One B-rep face of a CAD part: STEP entity #52636.
In plain terms, the planar face has unit normal (0, -0.174, 0.985).
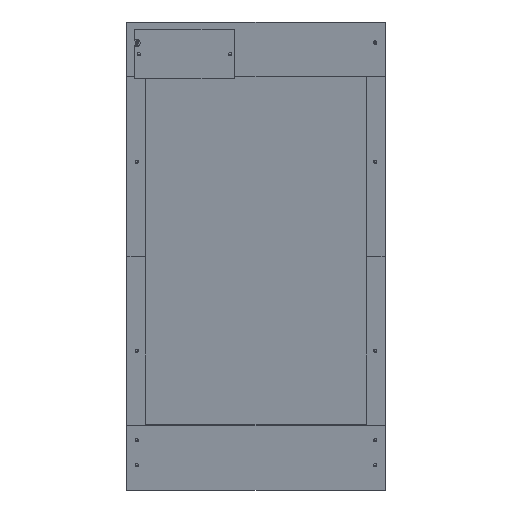
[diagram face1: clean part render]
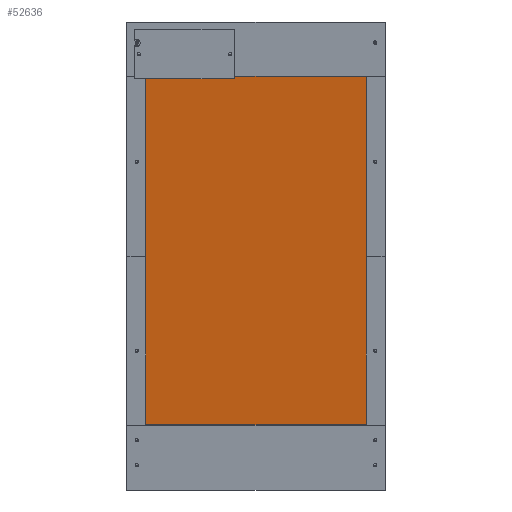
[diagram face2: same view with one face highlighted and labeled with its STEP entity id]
Its self-contained STEP definition (entity closure, numbers rounded to 3 decimals):
#52467 = PLANE('',#52468);
#52468 = AXIS2_PLACEMENT_3D('',#52469,#52470,#52471);
#52469 = CARTESIAN_POINT('',(18.1,64.,86.285));
#52470 = DIRECTION('',(-0.,1.,0.));
#52471 = DIRECTION('',(0.,0.,-1.));
#52495 = PLANE('',#52496);
#52496 = AXIS2_PLACEMENT_3D('',#52497,#52498,#52499);
#52497 = CARTESIAN_POINT('',(241.9,240.675,111.437));
#52498 = DIRECTION('',(1.,0.,0.));
#52499 = DIRECTION('',(-0.,0.,1.));
#52523 = PLANE('',#52524);
#52524 = AXIS2_PLACEMENT_3D('',#52525,#52526,#52527);
#52525 = CARTESIAN_POINT('',(18.1,417.349,136.59));
#52526 = DIRECTION('',(0.,-1.,0.));
#52527 = DIRECTION('',(0.,0.,1.));
#52549 = PLANE('',#52550);
#52550 = AXIS2_PLACEMENT_3D('',#52551,#52552,#52553);
#52551 = CARTESIAN_POINT('',(18.1,240.675,111.437));
#52552 = DIRECTION('',(1.,0.,0.));
#52553 = DIRECTION('',(-0.,0.,1.));
#52566 = VERTEX_POINT('',#52567);
#52567 = CARTESIAN_POINT('',(241.9,417.349,148.59));
#52588 = EDGE_CURVE('',#52589,#52566,#52591,.T.);
#52589 = VERTEX_POINT('',#52590);
#52590 = CARTESIAN_POINT('',(18.1,417.349,148.59));
#52591 = SURFACE_CURVE('',#52592,(#52596,#52603),.PCURVE_S1.);
#52592 = LINE('',#52593,#52594);
#52593 = CARTESIAN_POINT('',(18.1,417.349,148.59));
#52594 = VECTOR('',#52595,1.);
#52595 = DIRECTION('',(1.,0.,0.));
#52596 = PCURVE('',#52523,#52597);
#52597 = DEFINITIONAL_REPRESENTATION('',(#52598),#52602);
#52598 = LINE('',#52599,#52600);
#52599 = CARTESIAN_POINT('',(12.,0.));
#52600 = VECTOR('',#52601,1.);
#52601 = DIRECTION('',(0.,-1.));
#52602 = ( GEOMETRIC_REPRESENTATION_CONTEXT(2) 
PARAMETRIC_REPRESENTATION_CONTEXT() REPRESENTATION_CONTEXT('2D SPACE',''
  ) );
#52603 = PCURVE('',#52604,#52609);
#52604 = PLANE('',#52605);
#52605 = AXIS2_PLACEMENT_3D('',#52606,#52607,#52608);
#52606 = CARTESIAN_POINT('',(18.1,417.349,148.59));
#52607 = DIRECTION('',(0.,0.174,-0.985));
#52608 = DIRECTION('',(0.,-0.985,-0.174));
#52609 = DEFINITIONAL_REPRESENTATION('',(#52610),#52614);
#52610 = LINE('',#52611,#52612);
#52611 = CARTESIAN_POINT('',(0.,0.));
#52612 = VECTOR('',#52613,1.);
#52613 = DIRECTION('',(0.,-1.));
#52614 = ( GEOMETRIC_REPRESENTATION_CONTEXT(2) 
PARAMETRIC_REPRESENTATION_CONTEXT() REPRESENTATION_CONTEXT('2D SPACE',''
  ) );
#52636 = ADVANCED_FACE('',(#52637),#52604,.F.);
#52637 = FACE_BOUND('',#52638,.F.);
#52638 = EDGE_LOOP('',(#52639,#52640,#52663,#52686));
#52639 = ORIENTED_EDGE('',*,*,#52588,.T.);
#52640 = ORIENTED_EDGE('',*,*,#52641,.T.);
#52641 = EDGE_CURVE('',#52566,#52642,#52644,.T.);
#52642 = VERTEX_POINT('',#52643);
#52643 = CARTESIAN_POINT('',(241.9,64.,86.285));
#52644 = SURFACE_CURVE('',#52645,(#52649,#52656),.PCURVE_S1.);
#52645 = LINE('',#52646,#52647);
#52646 = CARTESIAN_POINT('',(241.9,417.349,148.59));
#52647 = VECTOR('',#52648,1.);
#52648 = DIRECTION('',(0.,-0.985,-0.174));
#52649 = PCURVE('',#52604,#52650);
#52650 = DEFINITIONAL_REPRESENTATION('',(#52651),#52655);
#52651 = LINE('',#52652,#52653);
#52652 = CARTESIAN_POINT('',(0.,-223.8));
#52653 = VECTOR('',#52654,1.);
#52654 = DIRECTION('',(1.,0.));
#52655 = ( GEOMETRIC_REPRESENTATION_CONTEXT(2) 
PARAMETRIC_REPRESENTATION_CONTEXT() REPRESENTATION_CONTEXT('2D SPACE',''
  ) );
#52656 = PCURVE('',#52495,#52657);
#52657 = DEFINITIONAL_REPRESENTATION('',(#52658),#52662);
#52658 = LINE('',#52659,#52660);
#52659 = CARTESIAN_POINT('',(37.152,-176.675));
#52660 = VECTOR('',#52661,1.);
#52661 = DIRECTION('',(-0.174,0.985));
#52662 = ( GEOMETRIC_REPRESENTATION_CONTEXT(2) 
PARAMETRIC_REPRESENTATION_CONTEXT() REPRESENTATION_CONTEXT('2D SPACE',''
  ) );
#52663 = ORIENTED_EDGE('',*,*,#52664,.F.);
#52664 = EDGE_CURVE('',#52665,#52642,#52667,.T.);
#52665 = VERTEX_POINT('',#52666);
#52666 = CARTESIAN_POINT('',(18.1,64.,86.285));
#52667 = SURFACE_CURVE('',#52668,(#52672,#52679),.PCURVE_S1.);
#52668 = LINE('',#52669,#52670);
#52669 = CARTESIAN_POINT('',(18.1,64.,86.285));
#52670 = VECTOR('',#52671,1.);
#52671 = DIRECTION('',(1.,0.,0.));
#52672 = PCURVE('',#52604,#52673);
#52673 = DEFINITIONAL_REPRESENTATION('',(#52674),#52678);
#52674 = LINE('',#52675,#52676);
#52675 = CARTESIAN_POINT('',(358.8,0.));
#52676 = VECTOR('',#52677,1.);
#52677 = DIRECTION('',(0.,-1.));
#52678 = ( GEOMETRIC_REPRESENTATION_CONTEXT(2) 
PARAMETRIC_REPRESENTATION_CONTEXT() REPRESENTATION_CONTEXT('2D SPACE',''
  ) );
#52679 = PCURVE('',#52467,#52680);
#52680 = DEFINITIONAL_REPRESENTATION('',(#52681),#52685);
#52681 = LINE('',#52682,#52683);
#52682 = CARTESIAN_POINT('',(0.,0.));
#52683 = VECTOR('',#52684,1.);
#52684 = DIRECTION('',(0.,-1.));
#52685 = ( GEOMETRIC_REPRESENTATION_CONTEXT(2) 
PARAMETRIC_REPRESENTATION_CONTEXT() REPRESENTATION_CONTEXT('2D SPACE',''
  ) );
#52686 = ORIENTED_EDGE('',*,*,#52687,.F.);
#52687 = EDGE_CURVE('',#52589,#52665,#52688,.T.);
#52688 = SURFACE_CURVE('',#52689,(#52693,#52700),.PCURVE_S1.);
#52689 = LINE('',#52690,#52691);
#52690 = CARTESIAN_POINT('',(18.1,417.349,148.59));
#52691 = VECTOR('',#52692,1.);
#52692 = DIRECTION('',(0.,-0.985,-0.174));
#52693 = PCURVE('',#52604,#52694);
#52694 = DEFINITIONAL_REPRESENTATION('',(#52695),#52699);
#52695 = LINE('',#52696,#52697);
#52696 = CARTESIAN_POINT('',(0.,0.));
#52697 = VECTOR('',#52698,1.);
#52698 = DIRECTION('',(1.,0.));
#52699 = ( GEOMETRIC_REPRESENTATION_CONTEXT(2) 
PARAMETRIC_REPRESENTATION_CONTEXT() REPRESENTATION_CONTEXT('2D SPACE',''
  ) );
#52700 = PCURVE('',#52549,#52701);
#52701 = DEFINITIONAL_REPRESENTATION('',(#52702),#52706);
#52702 = LINE('',#52703,#52704);
#52703 = CARTESIAN_POINT('',(37.152,-176.675));
#52704 = VECTOR('',#52705,1.);
#52705 = DIRECTION('',(-0.174,0.985));
#52706 = ( GEOMETRIC_REPRESENTATION_CONTEXT(2) 
PARAMETRIC_REPRESENTATION_CONTEXT() REPRESENTATION_CONTEXT('2D SPACE',''
  ) );
